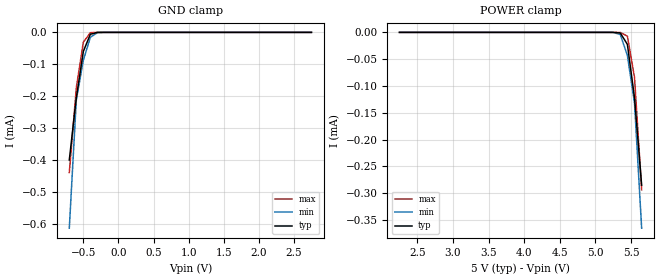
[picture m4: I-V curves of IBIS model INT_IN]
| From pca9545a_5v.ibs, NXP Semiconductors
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[Model]   INT_IN
Model_type Input
Vinh=2.1
Vinl=0.9
C_comp   1.73p   1.73p   1.73p
[Temperature Range] 27   85   -40
[Voltage Range]   5   4.5   5.5
[POWER Clamp Reference]5   4.5   5.5
[GND Clamp Reference]0   0   0
[GND Clamp]
-700mV    -399.2uA   -612.4uA   -438.7uA
-600mV    -204.8uA   -211.3uA   -173uA
-500mV    -59.42uA   -86.85uA   -30.5uA
-400mV    -5.924uA   -15.58uA   -1.042uA
-300mV    -169.2nA   -812.1nA   -11.13nA
-200mV    -2.901nA   -20.74nA   -88.93pA
2.75V     9.055pA    20.47pA    8.254pA
[POWER Clamp]
2.25V     9.055pA    20.47pA    8.254pA
5.15V     -361.3pA   -3.066nA   -8.065pA
5.25V     -22.74nA   -135.4nA   -1.008nA
5.35V     -1.121uA   -4.086uA   -115.4nA
5.45V     -22.41uA   -43.11uA   -7.05uA
5.55V     -122.1uA   -132.4uA   -84.24uA
5.65V     -285uA     -365.3uA   -293.6uA
